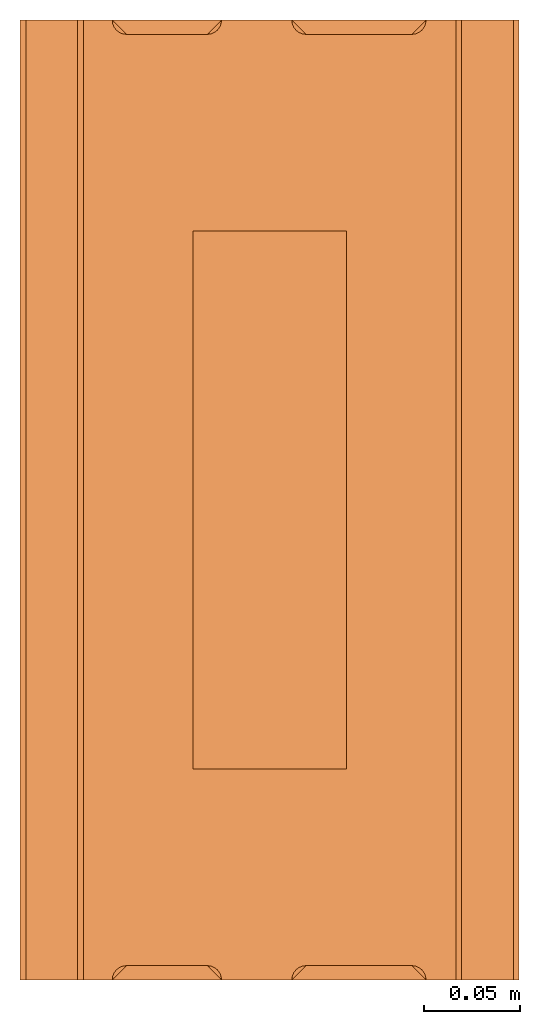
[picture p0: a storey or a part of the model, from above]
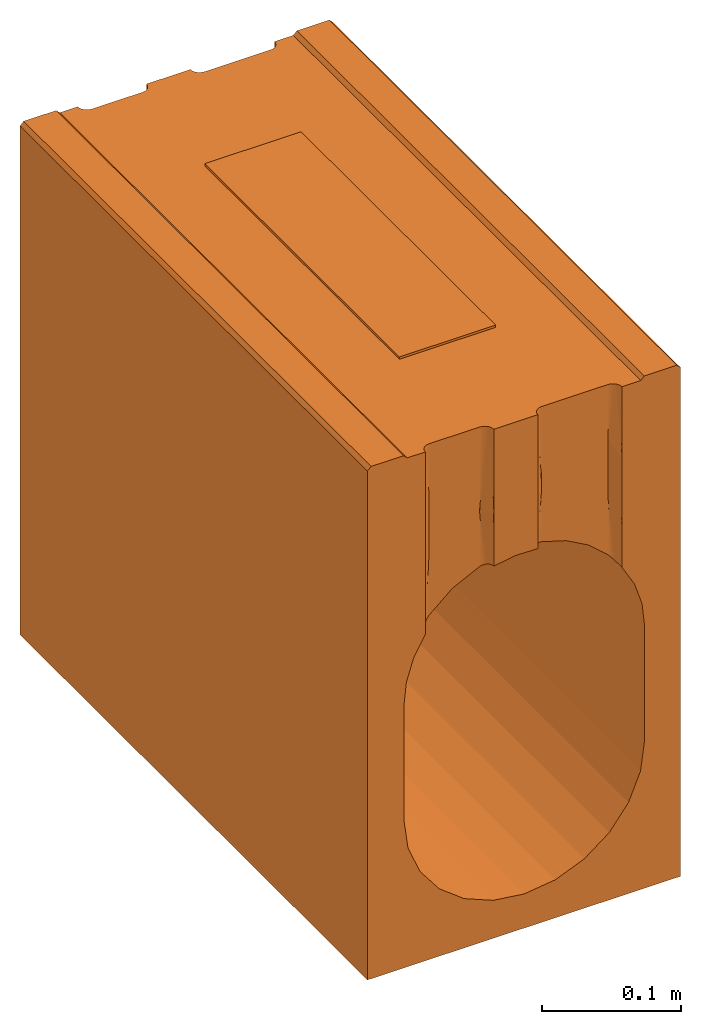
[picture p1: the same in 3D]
Properties of the parts of a building model (IFC2X3)

# File
Description: ViewDefinition [CoordinationView]
File name: 33203 - PD200 F 20.3 Rodding Access 500mm LG.ifc
Time: 2013-10-11T12:57:22
Written by: Autodesk Revit 2013
Made in: 20120221_2030(x64)

# IfcProject, Project Number
LongName: Project Name; Phase: Project Status

# IfcSite, Default
RefLatitude: 42, 21, 30, 344238; RefLongitude: -71, -3, -35, -194702; RefElevation: 0 mm

# IfcBuilding
Pset_BuildingCommon - NumberOfStoreys: 2
Other - Project Address: Enter address here; Project Issue Date: Issue Date; Project Name: Project Name; Client Name: Owner; Project Number: Project Number; Project Status: Project Status

# IfcBuildingStorey (2)
Constraints - Elevation Base: 0
Graphics - Symbol at End 2 Default: yes; Line Pattern: Center; Symbol: M_Level Head - Circle: M_Level Head - Circle; Symbol at End 1 Default: no; Line Weight: 1; Color: 0
Identity Data - Structural: no; Building Story: yes
Dimensions - Computation Height: 0 mm
Name | LongName = Name | Elevation (mm) = Constraints, Elevation (mm)
B.O. Footing | B.O. Footing | -4600
T.O. Footing | T.O. Footing | -4300

# IfcBuildingElementProxy: 33203 - PD200 F 20.3 Rodding Access 500mm LG, Civil-Drainage-Channel-ACO-RoadDrain 200:33203 - PD200 F 20.3 Rodding Access 500mm LG:33203 - PD200 F 20.3 Rodding Access 500mm LG:309971
In: B.O. Footing
Material: Acetal Resin, Black
Other - Revision: 1; CreatedBy: www.aco.co.uk
General - SerialNumber: 0.000000; TagNumber: 0.000000
Constraints - Level: Level: T.O. Footing; Moves With Nearby Elements: no
Phasing - Phase Created: Phase 1
Dimensions - Straight Void Length: 500 mm; Length: 500 mm; Custom Void Length: 0 mm; Volume: 32140659 mm3; Invert Depth.: 320 mm; Void Depth: -450 mm; Total Depth: 450 mm; Pipe Depth: 5800 mm; Straight Void Start: 0 mm; I/O End Cap Void: 3260 mm
Pset_BuildingElementProxyCommon - Reference: 33203 - PD200 F 20.3 Rodding Access 500mm LG
Construction - Access unit: yes; Closing End Cap: no; Channel 260mm Wide: no; Inlet Outlet end cap: no
Identity Data - Price: POA - contact ACO; Type Comments: ACO RoadDrain 200 PD200F 20.3 Constant Depth Access Channel 500mm Long; Model Description: Monolithic Channel drainage system; Installation guidelines: http://www.aco.co.uk/download.php?id=256; Address: ACO Business Park, Hitchin Road, Shefford, Bedfordshire, United Kingdom SG17 5TE; Product Code: 33203; Fax: +44 (0)1462 815895; Assembly Description: Rain Water Drainage; URL: www.aco.co.uk; Product brochure: http://www.aco.co.uk/download.php?id=256; Product Page URL: http://www.aco.co.uk/product_detail.php?id=21; Cost: 0; Manufacturer: ACO Technologies plc - ACO Water Management Division; Watermarked With: BIM Manager Premium Suite; Model: ACO RoadDrain 200 PD200F; Assembly Code: D2040; e-mail Technical: technical@aco.co.uk; Telephone: +44 (0)1462 816666; OmniClass Title: Rainwater Removal; Maintenance guidelines: http://www.aco.co.uk/download.php?id=256; e-mail Sales: customersupport@aco.co.uk; OmniClass Number: 23.70.50.24; Watermarked By: www.aco.co.uk; Watermark 2: This file is water marked and users are prohibited to reproduce, adapt, distribute this information; Watermark 1: This file is the property of ACO Technologies PLC
Materials and Finishes - Connection Pipe Material: N/A; Channel Material: Vienite® Synthetic Resin Concrete; End Cap Material: N/A; Access Cover/Frame Material: Ductile Iron; Channel Colour: Black; Grating Material: N/A; Grating Colour: N/A; Connection Pipe Colour: N/A; End Cap Colour: N/A; Grating Finish: N/A; Access Cover/Frame Colour: Black; Access Cover/Frame Finish: Water Based Paint Coating
Green Building Properties - Channel Recycled Material Content: 20% minimum; Access Cover/Frame Recyclable: Fully recyclable; End Cap Recyclable: N/A; Channel Recyclable: Fully recyclable; Access Cover/Frame Recycled Material Content: Between 40% - 90%; End Cap Recycled Material Content: N/A
Data - Product Weight: 53.5 Kg; Product Dimensions: 500mm x 260mm x 450mm (LxWxH); Invert Depth: 420mm; Concrete Surround Volume - Load Class F 900 - Concrete Pavement: 0.31m³/m; Load Class: A 15 - F 900; ACO Hydraulic Design Software: http://www.acodesign.co.uk; Connection Pipe O.D: N/A; Installation - Concrete Grade: Refer to brochure; Product Standard: BS EN 1433:2002, CE marked, Kitemarked; Hydraulic Performance: http://www.aco.co.uk/download.php?id=256; Channel C.S.A: 0.051m²

# IfcOpeningElement: Recess (2)
In: T.O. Footing
Constraints - Level: Level: T.O. Footing; Related to Mass: no; Height Offset From Level: 0 mm; Room Bounding: yes
Structural - Structural: no; Enable Analytical Model: no
Dimensions - Thickness: 1550 mm; Volume: 40257000000 mm3; Area: 26010000 mm2; Perimeter: 20400 mm
Phasing - Phase Created: Phase 1
Analytical Properties - Roughness: 1; Heat Transfer Coefficient (U): 0.558; Thermal Resistance (R): 1.79211; Absorptance: 0.1; Thermal mass: 2039700
Graphics - Coarse Scale Fill Color: 0
Construction - Default Thickness: 1550 mm; Function: 0
Materials and Finishes - Structural Material: Grass

# IfcSlab: Floor:Generic Floor - 400mm, Floor:Generic Floor - 400mm:136436
In: T.O. Footing
PredefinedType: FLOOR; Material: Grass 50 mm, Earth 1500 mm
Constraints - Level: Level: T.O. Footing; Related to Mass: no; Height Offset From Level: 0 mm; Room Bounding: yes
Structural - Structural: no; Enable Analytical Model: no
Dimensions - Thickness: 1550 mm; Volume: 40257000000 mm3; Area: 26010000 mm2; Perimeter: 20400 mm
Phasing - Phase Created: Phase 1
Pset_SlabCommon - Reference: Generic Floor - 400mm; IsExternal: no; LoadBearing: yes
Analytical Properties - Roughness: 1; Heat Transfer Coefficient (U): 0.558; Thermal Resistance (R): 1.79211; Absorptance: 0.1; Thermal mass: 2039700
Graphics - Coarse Scale Fill Color: 0
Construction - Default Thickness: 1550 mm; Function: 0
Materials and Finishes - Structural Material: Grass
